VERSION 5.7 ;
  NOWIREEXTENSIONATPIN ON ;
  DIVIDERCHAR "/" ;
  BUSBITCHARS "[]" ;
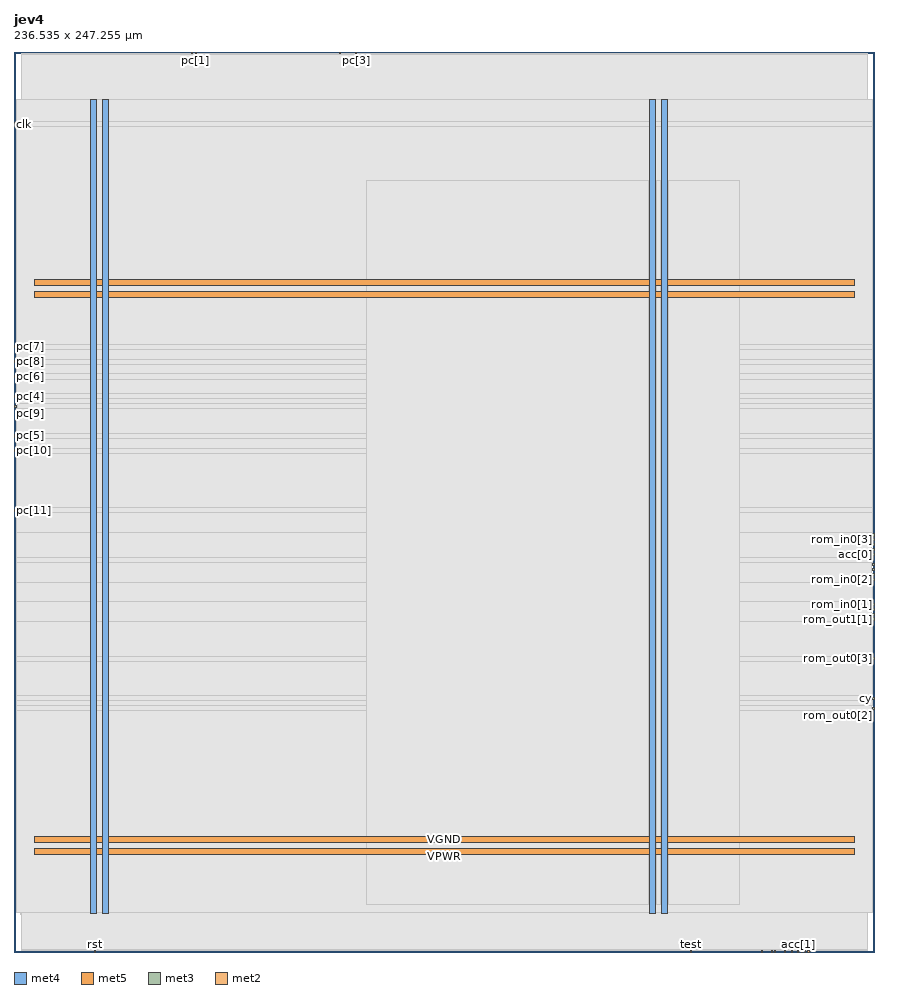
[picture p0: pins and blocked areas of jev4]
MACRO jev4
  CLASS BLOCK ;
  FOREIGN jev4 ;
  ORIGIN 0.000 0.000 ;
  SIZE 236.535 BY 247.255 ;
  PIN VGND
    DIRECTION INOUT ;
    USE GROUND ;
    PORT
      LAYER met4 ;
        RECT 24.340 10.640 25.940 234.160 ;
    END
    PORT
      LAYER met4 ;
        RECT 177.940 10.640 179.540 234.160 ;
    END
    PORT
      LAYER met5 ;
        RECT 5.520 30.030 230.920 31.630 ;
    END
    PORT
      LAYER met5 ;
        RECT 5.520 183.210 230.920 184.810 ;
    END
  END VGND
  PIN VPWR
    DIRECTION INOUT ;
    USE POWER ;
    PORT
      LAYER met4 ;
        RECT 21.040 10.640 22.640 234.160 ;
    END
    PORT
      LAYER met4 ;
        RECT 174.640 10.640 176.240 234.160 ;
    END
    PORT
      LAYER met5 ;
        RECT 5.520 26.730 230.920 28.330 ;
    END
    PORT
      LAYER met5 ;
        RECT 5.520 179.910 230.920 181.510 ;
    END
  END VPWR
  PIN acc[0]
    DIRECTION OUTPUT ;
    USE SIGNAL ;
    ANTENNADIFFAREA 0.383400 ;
    PORT
      LAYER met3 ;
        RECT 235.935 108.840 236.535 109.440 ;
    END
  END acc[0]
  PIN acc[1]
    DIRECTION OUTPUT ;
    USE SIGNAL ;
    ANTENNADIFFAREA 0.383400 ;
    PORT
      LAYER met2 ;
        RECT 215.370 0.000 215.650 0.280 ;
    END
  END acc[1]
  PIN acc[2]
    DIRECTION OUTPUT ;
    USE SIGNAL ;
    ANTENNADIFFAREA 0.383400 ;
    PORT
      LAYER met2 ;
        RECT 218.130 0.000 218.410 0.280 ;
    END
  END acc[2]
  PIN acc[3]
    DIRECTION OUTPUT ;
    USE SIGNAL ;
    ANTENNADIFFAREA 0.383400 ;
    PORT
      LAYER met2 ;
        RECT 216.290 0.000 216.570 0.280 ;
    END
  END acc[3]
  PIN clk
    DIRECTION INPUT ;
    USE SIGNAL ;
    ANTENNAGATEAREA 0.852000 ;
    PORT
      LAYER met3 ;
        RECT 0.000 227.160 0.600 227.760 ;
    END
  END clk
  PIN cy
    DIRECTION OUTPUT ;
    USE SIGNAL ;
    ANTENNADIFFAREA 0.383400 ;
    PORT
      LAYER met3 ;
        RECT 235.935 69.400 236.535 70.000 ;
    END
  END cy
  PIN pc[0]
    DIRECTION OUTPUT ;
    USE SIGNAL ;
    ANTENNADIFFAREA 0.383400 ;
    PORT
      LAYER met2 ;
        RECT 48.850 246.975 49.130 247.255 ;
    END
  END pc[0]
  PIN pc[10]
    DIRECTION OUTPUT ;
    USE SIGNAL ;
    ANTENNADIFFAREA 0.383400 ;
    PORT
      LAYER met3 ;
        RECT 0.000 137.400 0.600 138.000 ;
    END
  END pc[10]
  PIN pc[11]
    DIRECTION OUTPUT ;
    USE SIGNAL ;
    ANTENNADIFFAREA 0.383400 ;
    PORT
      LAYER met3 ;
        RECT 0.000 121.080 0.600 121.680 ;
    END
  END pc[11]
  PIN pc[1]
    DIRECTION OUTPUT ;
    USE SIGNAL ;
    ANTENNADIFFAREA 0.383400 ;
    PORT
      LAYER met2 ;
        RECT 49.770 246.975 50.050 247.255 ;
    END
  END pc[1]
  PIN pc[2]
    DIRECTION OUTPUT ;
    USE SIGNAL ;
    ANTENNADIFFAREA 0.383400 ;
    PORT
      LAYER met2 ;
        RECT 89.330 246.975 89.610 247.255 ;
    END
  END pc[2]
  PIN pc[3]
    DIRECTION OUTPUT ;
    USE SIGNAL ;
    ANTENNADIFFAREA 0.383400 ;
    PORT
      LAYER met2 ;
        RECT 93.930 246.975 94.210 247.255 ;
    END
  END pc[3]
  PIN pc[4]
    DIRECTION OUTPUT ;
    USE SIGNAL ;
    ANTENNADIFFAREA 0.383400 ;
    PORT
      LAYER met3 ;
        RECT 0.000 152.360 0.600 152.960 ;
    END
  END pc[4]
  PIN pc[5]
    DIRECTION OUTPUT ;
    USE SIGNAL ;
    ANTENNADIFFAREA 0.383400 ;
    PORT
      LAYER met3 ;
        RECT 0.000 141.480 0.600 142.080 ;
    END
  END pc[5]
  PIN pc[6]
    DIRECTION OUTPUT ;
    USE SIGNAL ;
    ANTENNADIFFAREA 0.383400 ;
    PORT
      LAYER met3 ;
        RECT 0.000 157.800 0.600 158.400 ;
    END
  END pc[6]
  PIN pc[7]
    DIRECTION OUTPUT ;
    USE SIGNAL ;
    ANTENNADIFFAREA 0.383400 ;
    PORT
      LAYER met3 ;
        RECT 0.000 165.960 0.600 166.560 ;
    END
  END pc[7]
  PIN pc[8]
    DIRECTION OUTPUT ;
    USE SIGNAL ;
    ANTENNADIFFAREA 0.383400 ;
    PORT
      LAYER met3 ;
        RECT 0.000 161.880 0.600 162.480 ;
    END
  END pc[8]
  PIN pc[9]
    DIRECTION OUTPUT ;
    USE SIGNAL ;
    ANTENNADIFFAREA 0.383400 ;
    PORT
      LAYER met3 ;
        RECT 0.000 149.640 0.600 150.240 ;
    END
  END pc[9]
  PIN ram_out[0]
    DIRECTION OUTPUT ;
    USE SIGNAL ;
    ANTENNADIFFAREA 0.383400 ;
    PORT
      LAYER met2 ;
        RECT 205.250 0.000 205.530 0.280 ;
    END
  END ram_out[0]
  PIN ram_out[1]
    DIRECTION OUTPUT ;
    USE SIGNAL ;
    ANTENNADIFFAREA 0.383400 ;
    PORT
      LAYER met2 ;
        RECT 213.530 0.000 213.810 0.280 ;
    END
  END ram_out[1]
  PIN ram_out[2]
    DIRECTION OUTPUT ;
    USE SIGNAL ;
    ANTENNADIFFAREA 0.383400 ;
    PORT
      LAYER met2 ;
        RECT 211.690 0.000 211.970 0.280 ;
    END
  END ram_out[2]
  PIN ram_out[3]
    DIRECTION OUTPUT ;
    USE SIGNAL ;
    ANTENNADIFFAREA 0.383400 ;
    PORT
      LAYER met2 ;
        RECT 208.010 0.000 208.290 0.280 ;
    END
  END ram_out[3]
  PIN rom_in0[0]
    DIRECTION INPUT ;
    USE SIGNAL ;
    ANTENNAGATEAREA 0.196500 ;
    PORT
      LAYER met3 ;
        RECT 235.935 110.200 236.535 110.800 ;
    END
  END rom_in0[0]
  PIN rom_in0[1]
    DIRECTION INPUT ;
    USE SIGNAL ;
    ANTENNAGATEAREA 0.196500 ;
    PORT
      LAYER met3 ;
        RECT 235.935 95.240 236.535 95.840 ;
    END
  END rom_in0[1]
  PIN rom_in0[2]
    DIRECTION INPUT ;
    USE SIGNAL ;
    ANTENNAGATEAREA 0.196500 ;
    PORT
      LAYER met3 ;
        RECT 235.935 102.040 236.535 102.640 ;
    END
  END rom_in0[2]
  PIN rom_in0[3]
    DIRECTION INPUT ;
    USE SIGNAL ;
    ANTENNAGATEAREA 0.196500 ;
    PORT
      LAYER met3 ;
        RECT 235.935 112.920 236.535 113.520 ;
    END
  END rom_in0[3]
  PIN rom_in1[0]
    DIRECTION INPUT ;
    USE SIGNAL ;
    ANTENNAGATEAREA 0.196500 ;
    PORT
      LAYER met3 ;
        RECT 235.935 111.560 236.535 112.160 ;
    END
  END rom_in1[0]
  PIN rom_in1[1]
    DIRECTION INPUT ;
    USE SIGNAL ;
    ANTENNAGATEAREA 0.196500 ;
    PORT
      LAYER met3 ;
        RECT 235.935 93.880 236.535 94.480 ;
    END
  END rom_in1[1]
  PIN rom_in1[2]
    DIRECTION INPUT ;
    USE SIGNAL ;
    ANTENNAGATEAREA 0.196500 ;
    PORT
      LAYER met3 ;
        RECT 235.935 103.400 236.535 104.000 ;
    END
  END rom_in1[2]
  PIN rom_in1[3]
    DIRECTION INPUT ;
    USE SIGNAL ;
    ANTENNAGATEAREA 0.196500 ;
    PORT
      LAYER met3 ;
        RECT 235.935 114.280 236.535 114.880 ;
    END
  END rom_in1[3]
  PIN rom_out0[0]
    DIRECTION OUTPUT ;
    USE SIGNAL ;
    ANTENNADIFFAREA 0.383400 ;
    PORT
      LAYER met2 ;
        RECT 208.930 0.000 209.210 0.280 ;
    END
  END rom_out0[0]
  PIN rom_out0[1]
    DIRECTION OUTPUT ;
    USE SIGNAL ;
    ANTENNADIFFAREA 0.383400 ;
    PORT
      LAYER met2 ;
        RECT 217.210 0.000 217.490 0.280 ;
    END
  END rom_out0[1]
  PIN rom_out0[2]
    DIRECTION OUTPUT ;
    USE SIGNAL ;
    ANTENNADIFFAREA 0.383400 ;
    PORT
      LAYER met3 ;
        RECT 235.935 66.680 236.535 67.280 ;
    END
  END rom_out0[2]
  PIN rom_out0[3]
    DIRECTION OUTPUT ;
    USE SIGNAL ;
    ANTENNADIFFAREA 0.383400 ;
    PORT
      LAYER met3 ;
        RECT 235.935 80.280 236.535 80.880 ;
    END
  END rom_out0[3]
  PIN rom_out1[0]
    DIRECTION OUTPUT ;
    USE SIGNAL ;
    ANTENNADIFFAREA 0.383400 ;
    PORT
      LAYER met3 ;
        RECT 235.935 104.760 236.535 105.360 ;
    END
  END rom_out1[0]
  PIN rom_out1[1]
    DIRECTION OUTPUT ;
    USE SIGNAL ;
    ANTENNADIFFAREA 0.383400 ;
    PORT
      LAYER met3 ;
        RECT 235.935 91.160 236.535 91.760 ;
    END
  END rom_out1[1]
  PIN rom_out1[2]
    DIRECTION OUTPUT ;
    USE SIGNAL ;
    ANTENNADIFFAREA 0.383400 ;
    PORT
      LAYER met3 ;
        RECT 235.935 92.520 236.535 93.120 ;
    END
  END rom_out1[2]
  PIN rom_out1[3]
    DIRECTION OUTPUT ;
    USE SIGNAL ;
    ANTENNADIFFAREA 0.383400 ;
    PORT
      LAYER met3 ;
        RECT 235.935 106.120 236.535 106.720 ;
    END
  END rom_out1[3]
  PIN rst
    DIRECTION INPUT ;
    USE SIGNAL ;
    ANTENNAGATEAREA 0.196500 ;
    PORT
      LAYER met2 ;
        RECT 22.170 0.000 22.450 0.280 ;
    END
  END rst
  PIN test
    DIRECTION INPUT ;
    USE SIGNAL ;
    ANTENNAGATEAREA 0.196500 ;
    PORT
      LAYER met2 ;
        RECT 185.930 0.000 186.210 0.280 ;
    END
  END test
  OBS
      LAYER nwell ;
        RECT 5.330 10.795 231.110 234.005 ;
      LAYER li1 ;
        RECT 5.520 10.795 230.920 234.005 ;
      LAYER met1 ;
        RECT 1.910 10.240 234.530 234.160 ;
      LAYER met2 ;
        RECT 1.930 246.695 48.570 246.975 ;
        RECT 49.410 246.695 49.490 246.975 ;
        RECT 50.330 246.695 89.050 246.975 ;
        RECT 89.890 246.695 93.650 246.975 ;
        RECT 94.490 246.695 234.510 246.975 ;
        RECT 1.930 0.560 234.510 246.695 ;
        RECT 1.930 0.280 21.890 0.560 ;
        RECT 22.730 0.280 185.650 0.560 ;
        RECT 186.490 0.280 204.970 0.560 ;
        RECT 205.810 0.280 207.730 0.560 ;
        RECT 208.570 0.280 208.650 0.560 ;
        RECT 209.490 0.280 211.410 0.560 ;
        RECT 212.250 0.280 213.250 0.560 ;
        RECT 214.090 0.280 215.090 0.560 ;
        RECT 215.930 0.280 216.010 0.560 ;
        RECT 216.850 0.280 216.930 0.560 ;
        RECT 217.770 0.280 217.850 0.560 ;
        RECT 218.690 0.280 234.510 0.560 ;
      LAYER met3 ;
        RECT 0.600 228.160 235.935 234.085 ;
        RECT 1.000 226.760 235.935 228.160 ;
        RECT 0.600 166.960 235.935 226.760 ;
        RECT 1.000 165.560 235.935 166.960 ;
        RECT 0.600 162.880 235.935 165.560 ;
        RECT 1.000 161.480 235.935 162.880 ;
        RECT 0.600 158.800 235.935 161.480 ;
        RECT 1.000 157.400 235.935 158.800 ;
        RECT 0.600 153.360 235.935 157.400 ;
        RECT 1.000 151.960 235.935 153.360 ;
        RECT 0.600 150.640 235.935 151.960 ;
        RECT 1.000 149.240 235.935 150.640 ;
        RECT 0.600 142.480 235.935 149.240 ;
        RECT 1.000 141.080 235.935 142.480 ;
        RECT 0.600 138.400 235.935 141.080 ;
        RECT 1.000 137.000 235.935 138.400 ;
        RECT 0.600 122.080 235.935 137.000 ;
        RECT 1.000 120.680 235.935 122.080 ;
        RECT 0.600 115.280 235.935 120.680 ;
        RECT 0.600 108.440 235.535 115.280 ;
        RECT 0.600 107.120 235.935 108.440 ;
        RECT 0.600 101.640 235.535 107.120 ;
        RECT 0.600 96.240 235.935 101.640 ;
        RECT 0.600 90.760 235.535 96.240 ;
        RECT 0.600 81.280 235.935 90.760 ;
        RECT 0.600 79.880 235.535 81.280 ;
        RECT 0.600 70.400 235.935 79.880 ;
        RECT 0.600 69.000 235.535 70.400 ;
        RECT 0.600 67.680 235.935 69.000 ;
        RECT 0.600 66.280 235.535 67.680 ;
        RECT 0.600 10.715 235.935 66.280 ;
      LAYER met4 ;
        RECT 96.895 13.095 174.240 211.985 ;
        RECT 176.640 13.095 177.540 211.985 ;
        RECT 179.940 13.095 199.345 211.985 ;
  END
END jev4
END LIBRARY

